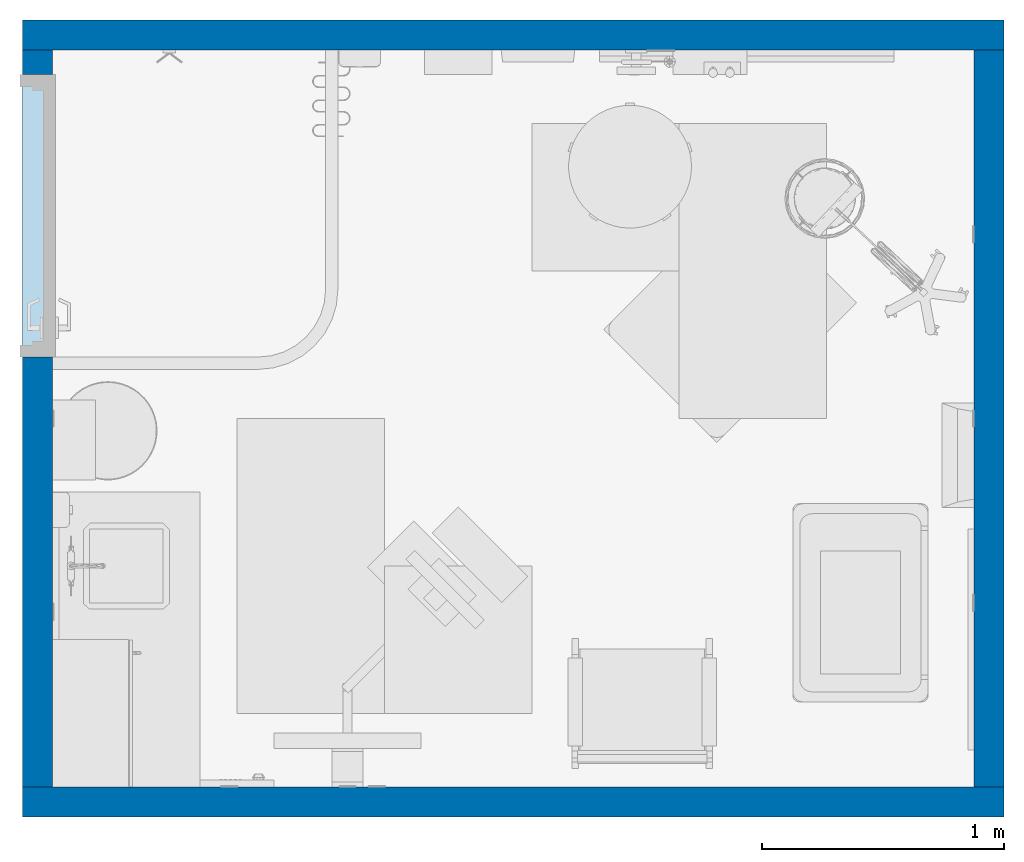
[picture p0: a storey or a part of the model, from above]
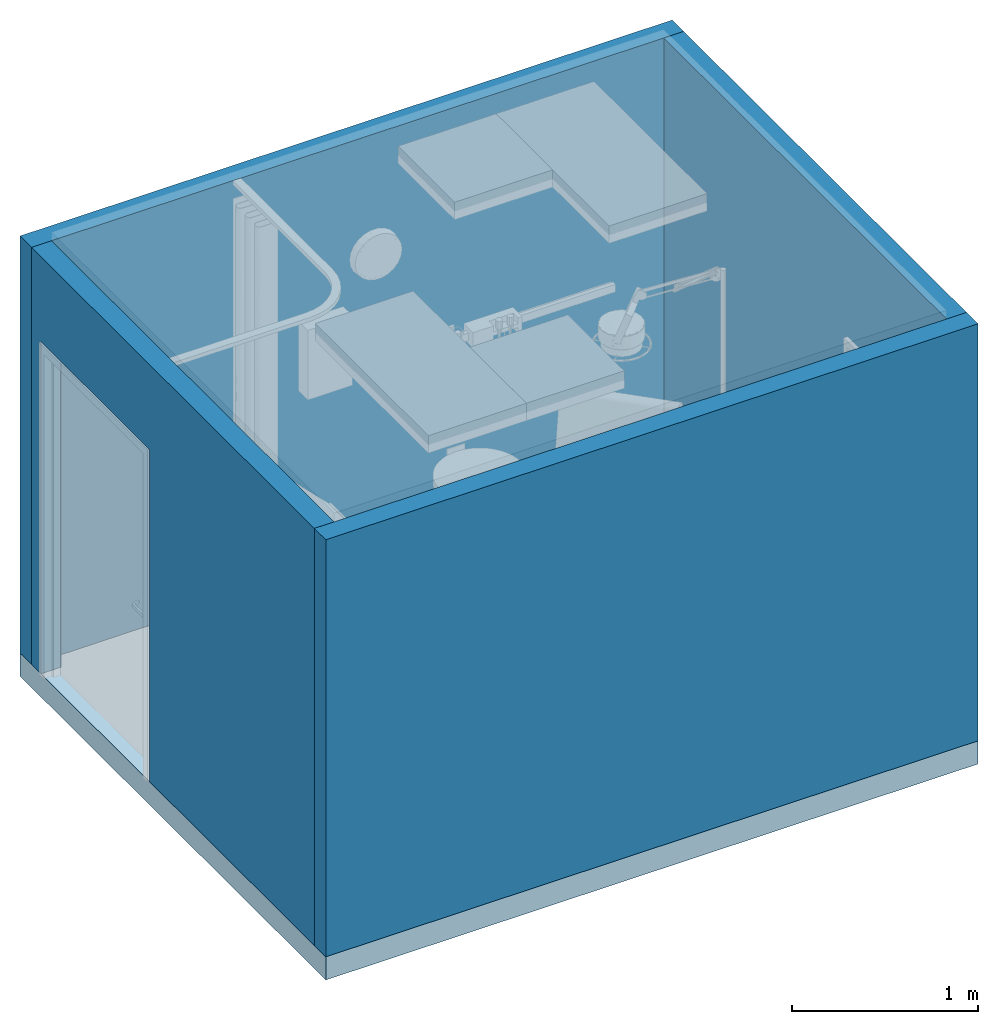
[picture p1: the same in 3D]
Properties of the parts of a building model (IFC2X3)

# File
Description: ViewDefinition [CoordinationView_V2.0]
File name: (ROOM CODE)
Time: 2018-06-28T07:31:28
Written by: The EXPRESS Data Manager Version 5.02.0100.07 : 28 Aug 2013
Made in: 20170223_1515(x64) - Exporter 18.0.0.420 - Alternate UI 18.0.0.420
Comment: STEP Physical File produced by: The EXPRESS Data Manager Version 5.02.0100.07 : 28 Aug 2013 * Module: EDMstepFileFactory/EDMstandAlone * Creation date: Thu Jun 28 07:31:28 2018 * Host: L106-OKC * Database: C:\Users\BHR~1.SPU\AppData\Local\Temp\{FAD27B77-2280-448A-A3FB-40F2C8162BD9}\ifc * Database version: 5507 * Database creation date: Thu Jun 28 07:31:26 2018 * Schema: IFC2X3 * Model: DataRepository.ifc * Model creation date: Thu Jun 28 07:31:26 2018 * Header model: DataRepository.ifc_HeaderModel * Header model creation date: Thu Jun 28 07:31:26 2018 * EDMuser: sdai-user * EDMgroup: sdai-group * License ID and type: 5605 : Permanent license. Expiry date: * EDMstepFileFactory options: 020000

# IfcProject, (ROOM CODE)
LongName: ROOM NAME (ROOM CODE); Phase: DRAFT

# IfcSite, Default
RefLatitude: 42, 21, 31, 181945; RefLongitude: -71, -3, -24, -263305; RefElevation: 0 ft

# IfcBuilding, OUTPATIENT / PACT CLINIC (Ch. 265)
LongName: OUTPATIENT / PACT CLINIC (Ch. 265)
Pset_BuildingCommon - NumberOfStoreys: 1

# IfcBuildingStorey, DATUM
In: OUTPATIENT / PACT CLINIC (Ch. 265)
LongName: DATUM; Elevation: 0 ft

# IfcSpace, WRTM3
In: DATUM
LongName: TELE-RETINAL ROOM; InteriorOrExteriorSpace: INTERNAL
Pset_SpaceCommon - Reference: TELE-RETINAL ROOM WRTM3; Category: Rooms

# IfcBuildingElementProxy: 24" x 24", Supply Diffuser:24" x 24":1103943
In: WRTM3
Type - Classification: D3040100 Air Distribution Systems (Uniformat)
Pset_BuildingElementProxyCommon - Reference: 24" x 24"

# IfcBuildingElementProxy: 24" x 24", Return Register:24" x 24":927408
In: WRTM3
Type - Classification: D3040200 Exhaust Ventilation Systems (Uniformat)
Pset_BuildingElementProxyCommon - Reference: 24" x 24"

# IfcBuildingElementProxy: 24"H x 10 1/2"D x 24"W Key Alike, Z1020 - Cabinet WH-1 DO - Right:24"H x 10 1/2"D x 24"W Key Alike:1892893
In: WRTM3
Type - Classification: CC (Uniformat)
Pset_BuildingElementProxyCommon - Reference: 24"H x 10 1/2"D x 24"W Key Alike
Pset_ManufacturerTypeInformation - Manufacturer: Herman Miller, Inc.

# IfcBuildingElementProxy: A1012 - Telephone, Wall Mounted, 1 Line 12'' x 12'', A1012 - Telephone, Wall Mounted, 1 Line:A1012 - Telephone, Wall Mounted, 1 Line 12'' x 12'':1641367
In: WRTM3
Type - Classification: VV (Uniformat)
Pset_BuildingElementProxyCommon - Reference: A1012 - Telephone, Wall Mounted, 1 Line 12'' x 12''

# IfcBuildingElementProxy: A1132 - Rail, Accessory Mounting, A1132 - Rail, Accessory Mounting:A1132 - Rail, Accessory Mounting:1641386
In: WRTM3
Type - Classification: VC (Uniformat)
Pset_BuildingElementProxyCommon - Reference: A1132 - Rail, Accessory Mounting

# IfcBuildingElementProxy: A5075 - Dispenser, Soap, A5075 - Dispenser, Soap:A5075 - Dispenser, Soap:1641368
In: WRTM3
Type - Classification: VV (Uniformat)
Pset_BuildingElementProxyCommon - Reference: A5075 - Dispenser, Soap

# IfcBuildingElementProxy: A5077 - Dispenser, Hand Sanitizer, Hands free 7"x 3", A5077 - Dispenser, Hand Sanitizer, Hands free:A5077 - Dispenser, Hand Sanitizer, Hands free 7"x 3":1641390
In: WRTM3
Type - Classification: VV (Uniformat)
Pset_BuildingElementProxyCommon - Reference: A5077 - Dispenser, Hand Sanitizer, Hands free 7"x 3"

# IfcBuildingElementProxy: A5080 - Dispenser, Paper Towel, A5080 - Dispenser, Paper Towel:A5080 - Dispenser, Paper Towel:1641369
In: WRTM3
Type - Classification: CC (Uniformat)
Pset_BuildingElementProxyCommon - Reference: A5080 - Dispenser, Paper Towel

# IfcBuildingElementProxy: A5107 - Dispenser, Glove, Surgical-Examination, Wall Mntd 10"x 4", A5107 - Dispenser, Glove, Surgical-Examination, Wall Mntd:A5107 - Dispenser, Glove, Surgical-Examination, Wall Mntd 10"x 4":1641387
In: WRTM3
Classification: VV (Uniformat)
Pset_BuildingElementProxyCommon - Reference: A5107 - Dispenser, Glove, Surgical-Examination, Wall Mntd 10"x 4"

# IfcBuildingElementProxy: A5108 - Waste Disposal Unit, Sharps 17"x 13", A5108 - Waste Disposal Unit, Sharps:A5108 - Waste Disposal Unit, Sharps 17"x 13":1641391
In: DATUM
Type - Classification: VV (Uniformat)
Pset_BuildingElementProxyCommon - Reference: A5108 - Waste Disposal Unit, Sharps 17"x 13"

# IfcBuildingElementProxy: A5145 - Hook, Garment, Double, A5145 - Hook, Garment, Double:A5145 - Hook, Garment, Double:1641370
In: WRTM3
Type - Classification: CC (Uniformat)
Pset_BuildingElementProxyCommon - Reference: A5145 - Hook, Garment, Double

# IfcBuildingElementProxy: A5180 - Track, Cubicle, Surface Mounted, With Curtain, Curved, A5180 - Track, Cubicle, Surface Mounted, With Curtain, Corner:A5180 - Track, Cubicle, Surface Mounted, With Curtain, Curved:1641388
In: WRTM3
Type - Classification: CC (Uniformat)
Pset_BuildingElementProxyCommon - Reference: A5180 - Track, Cubicle, Surface Mounted, With Curtain, Curved

# IfcBuildingElementProxy: CS010 - Sink, SS, Single Compartment, 7.5x12x12 ID, CS010 - Sink, SS, Single Compartment, 7.5x12x12 ID:CS010 - Sink, SS, Single Compartment, 7.5x12x12 ID:1641371
In: WRTM3
Type - Classification: CC (Uniformat)
Pset_BuildingElementProxyCommon - Reference: CS010 - Sink, SS, Single Compartment, 7.5x12x12 ID

# IfcBuildingElementProxy: CT020 - Countertop, Solid Surface, CT020 - Countertop, Solid Surface:CT020 - Countertop, Solid Surface:1641372
In: WRTM3
Type - Classification: CC (Uniformat)
Pset_BuildingElementProxyCommon - Reference: CT020 - Countertop, Solid Surface

# IfcBuildingElementProxy: Duplex (6)
In: WRTM3
Pset_BuildingElementProxyCommon - Reference: Duplex
Name (Outlet, Duplex, Wall:Duplex:...)
1641394
1641396
1641397
1641399
1641400
1641401

# IfcBuildingElementProxy: E0948 - Cart, General Storage, Mobile 42x32x22, E0948 - Cart, General Storage, Mobile 42x32x22:E0948 - Cart, General Storage, Mobile 42x32x22:1641373
In: WRTM3
Type - Classification: VV (Uniformat)
Pset_BuildingElementProxyCommon - Reference: E0948 - Cart, General Storage, Mobile 42x32x22

# IfcBuildingElementProxy: Exam/Treatment Table with Cabinet, M9025 - Exam Table:Exam/Treatment Table with Cabinet:1641384
In: WRTM3
Type - Classification: VV (Uniformat)
Pset_BuildingElementProxyCommon - Reference: Exam/Treatment Table with Cabinet

# IfcBuildingElementProxy: F0205 - Chair, Side With Arms, F0205 - Chair, Side With Arms:F0205 - Chair, Side With Arms:1641374
In: WRTM3
Type - Classification: VV (Uniformat)
Pset_BuildingElementProxyCommon - Reference: F0205 - Chair, Side With Arms

# IfcBuildingElementProxy: F0340 - Stool, Self Adjusting, F0340 - Stool, Self Adjusting:F0340 - Stool, Self Adjusting:1641375
In: WRTM3
Type - Classification: VV (Uniformat)
Pset_BuildingElementProxyCommon - Reference: F0340 - Stool, Self Adjusting

# IfcBuildingElementProxy: F2000 - Basket, Wastepaper, F2000 - Basket, Wastepaper:F2000 - Basket, Wastepaper:1641376
In: WRTM3
Type - Classification: VV (Uniformat)
Pset_BuildingElementProxyCommon - Reference: F2000 - Basket, Wastepaper

# IfcBuildingElementProxy: F3025 - Board, Bulletin, Wood Framed, F3025 - Board, Bulletin, Wood Framed:F3025 - Board, Bulletin, Wood Framed:1641377
In: WRTM3
Type - Classification: VV (Uniformat)
Pset_BuildingElementProxyCommon - Reference: F3025 - Board, Bulletin, Wood Framed

# IfcBuildingElementProxy: F3200 - Clock, Battery, 12in Dia, F3200 - Clock, Battery, 12in Dia:F3200 - Clock, Battery, 12in Dia:1641378
In: WRTM3
Type - Classification: VV (Uniformat)
Pset_BuildingElementProxyCommon - Reference: F3200 - Clock, Battery, 12in Dia

# IfcBuildingElementProxy: M0506 - Television, Flat Screen, M0506 - Television, Flat Screen:M0506 - Television, Flat Screen:1641392
In: WRTM3
Type - Classification: VV (Uniformat)
Pset_BuildingElementProxyCommon - Reference: M0506 - Television, Flat Screen

# IfcBuildingElementProxy: M1801 - Computer with Flat Panel Monitor, M1801 - Computer with Flat Panel Monitor:M1801 - Computer with Flat Panel Monitor:1641379
In: WRTM3
Type - Classification: VV (Uniformat)
Pset_BuildingElementProxyCommon - Reference: M1801 - Computer with Flat Panel Monitor

# IfcBuildingElementProxy: M1803 - Workstation, Computer, Wall Mounted, M1803 - Workstation, Computer, Wall Mounted:M1803 - Workstation, Computer, Wall Mounted:1641380
In: WRTM3
Type - Classification: VV (Uniformat)
Pset_BuildingElementProxyCommon - Reference: M1803 - Workstation, Computer, Wall Mounted

# IfcBuildingElementProxy: M4100 - Sphygmomanometer, Aneroid, Wall-Mounted, M4100 - Sphygmomanometer, Aneroid, Wall-Mounted:M4100 - Sphygmomanometer, Aneroid, Wall-Mounted:1641381
In: WRTM3
Type - Classification: VV (Uniformat)
Pset_BuildingElementProxyCommon - Reference: M4100 - Sphygmomanometer, Aneroid, Wall-Mounted

# IfcBuildingElementProxy: M4200 - Otoscope_Ophthalmoscope, Wall Mounted, M4200 - Otoscope_Ophthalmoscope, Wall Mounted:M4200 - Otoscope_Ophthalmoscope, Wall Mounted:1641382
In: WRTM3
Type - Classification: VV (Uniformat)
Pset_BuildingElementProxyCommon - Reference: M4200 - Otoscope_Ophthalmoscope, Wall Mounted

# IfcBuildingElementProxy: M6050 - Retinal Imaging System, M6050 - Retinal Imaging System:M6050 - Retinal Imaging System:1641434
In: WRTM3
Type - Classification: VV (Uniformat)
Pset_BuildingElementProxyCommon - Reference: M6050 - Retinal Imaging System

# IfcBuildingElementProxy: Mobile Spotlight, Mobile Stand, M7401 - Exam Light:Mobile Spotlight, Mobile Stand:1641383
In: WRTM3
Type - Classification: VV (Uniformat)
Pset_BuildingElementProxyCommon - Reference: Mobile Spotlight, Mobile Stand

# IfcBuildingElementProxy: Quadraplex, Outlet, Quadraplex, Wall:Quadraplex:1641398
In: WRTM3
Pset_BuildingElementProxyCommon - Reference: Quadraplex

# IfcBuildingElementProxy: Telephone/Data (2)
In: WRTM3
Pset_BuildingElementProxyCommon - Reference: Telephone/Data
Name (Outlet, Communications:Telephone/Data:...)
1641395
1734433

# IfcCovering: Compound Ceiling:2' x 2' ACT System, Compound Ceiling:2' x 2' ACT System:927386
In: DATUM
PredefinedType: CEILING; Classification: C3030210 Suspended Ceilings - Acoustical (Uniformat); Material: <Unnamed> 0.135417 ft, Acoustic Ceiling Tile 24 x 24 0.0520833 ft
Pset_CoveringCommon - Reference: 2' x 2' ACT System; Finish: Acoustic Ceiling Tile 24 x 24;; TotalThickness: 0.1875 ft

# IfcDoor: 42" x 84", Single - Flush:42" x 84":1641393
In: DATUM
Type - ParameterTakesPrecedence: no; Sizeable: no; Classification: C1020 Interior Doors (Uniformat)
OverallHeight: 7.16667 ft; OverallWidth: 3.83333 ft
Pset_DoorCommon - IsExternal: no; Reference: 42" x 84"

# IfcFlowTerminal: 2'x4' (2)
In: WRTM3
Type - Classification: D5020210 Lighting - Fluorescent (Uniformat)
Pset_DistributionFlowElementCommon - Reference: 2'x4'
Name (Troffer Light:2'x4':...)
1103301
1103756

# IfcSlab: Floor:Generic - 6", Floor:Generic - 6":1641362
In: DATUM
PredefinedType: FLOOR; Classification: B1010 Floor Construction (Uniformat); Material: <Unnamed> 0.5 ft
Pset_SlabCommon - LoadBearing: no; Reference: Generic - 6"; IsExternal: no; PitchAngle: 0 deg

# IfcWallStandardCase: Basic Wall:Interior - 4 7/8" (4)
In: DATUM
Type - PredefinedType: STANDARD; Material: <Unnamed> 0.40625 ft
Classification: B2010 Exterior Walls (Uniformat)
Pset_WallCommon - Reference: Interior - 4 7/8"; LoadBearing: no; ExtendToStructure: no; IsExternal: yes
Name (Basic Wall:Interior - 4 7/8":...)
1641356
1641357
1641358
1641359
